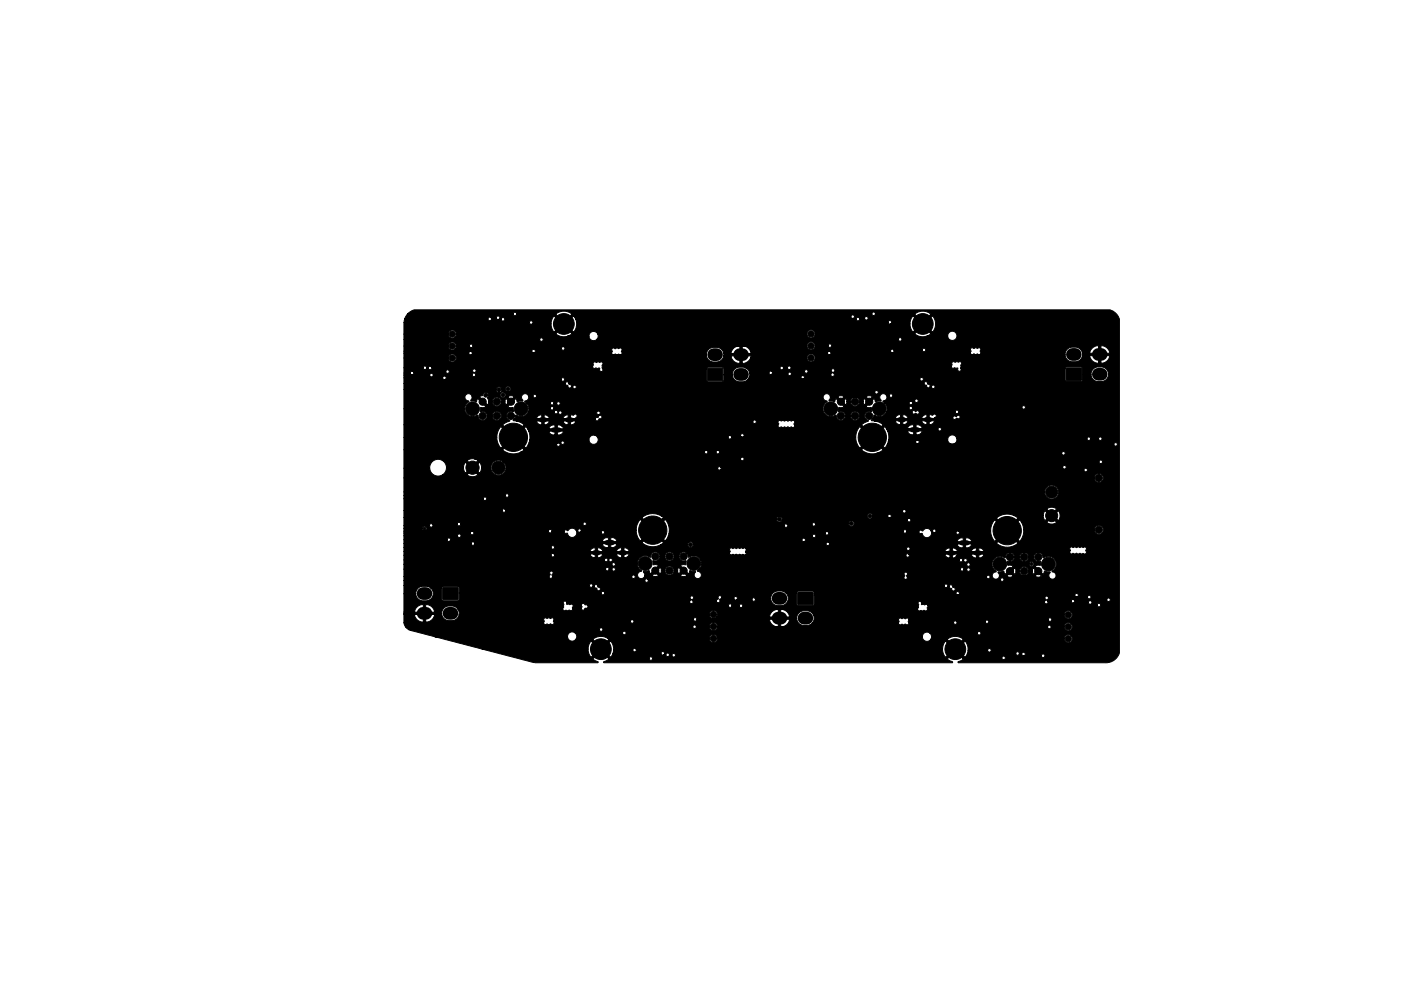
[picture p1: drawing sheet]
<svg xmlns="http://www.w3.org/2000/svg" width="297mm" height="210mm" viewBox="0 0 297 210" stroke-linecap="round" stroke-linejoin="round" font-family="sans-serif">
<g fill="#000" stroke="#000" stroke-width=".21">
<path d="M86.4 66.6l.7-.6 .8-.3 147.6 .1a2.97 2.97 0 0 1 1.8 1.9v70.8a2.99 2.99 0 0 1-2.8 2.1h-31.3l-.1-.1 1.2-.7-.3-.2h8.4a.38 .38 0 0 0 .5 .3 .38 .38 0 0 0 .1-.6 .38 .38 0 0 0-.6 .2v.1h-8.4l-1.5-1.5-1.7 1.7 1.2 .6-.1 .2h-73.8l-.1-.1 .9-.5 .2-.2-.1-.1h8.6a.38 .38 0 0 0 .5 .4 .38 .38 0 0 0 .1-.7 .38 .38 0 0 0-.6 .2v.1h-8.6l-1.6-1.6-1.7 1.7 1.1 .6-.1 .2h-13.2l-11.3-2.9h22.5l.1 1 .5 .8 1.7-1.8h.8l1.7 1.8 .5-.9h10.1l.3 .4 .8-.1v.1a.37 .37 0 0 0 .4 .3 .37 .37 0 0 0 .3-.3h.6v.1a.38 .38 0 0 0 .6 .2 .38 .38 0 0 0-.1-.6 .38 .38 0 0 0-.5 .3l-.6-.1a.38 .38 0 0 0-.3-.3 .38 .38 0 0 0-.4 .3h-.5a.37 .37 0 0 0 0-.6 .37 .37 0 0 0-.6 .3h-10.1l.1-.7h4.1v.1a.37 .37 0 0 0 .5 .3 .37 .37 0 0 0 .2-.6h64.9l.2 1 .5 .8 1.7-1.8h.7l1.7 1.8 .5-.8h10.3a.37 .37 0 0 0 .3 .3 .37 .37 0 0 0 .4-.2h.5l.4 .3h3.8a.38 .38 0 0 0 .5 .4 .38 .38 0 0 0 .1-.7 .38 .38 0 0 0-.6 .2v.1h-3.7a.38 .38 0 0 0 .1-.6 .38 .38 0 0 0-.6 .3h-.5a.38 .38 0 0 0-.3-.5 .38 .38 0 0 0-.4 .4h-10.3l.1-.7h4.2v.1a.38 .38 0 0 0 .6 .1 .38 .38 0 0 0-.1-.6 .38 .38 0 0 0-.5 .4h-4.2l-.1-1.2-.5-.8-1.7 1.7h-.7l-1.7-1.7-.5 .8-.2 .9h-64.9l-.4-.2-.3 .4h-4.1a2.63 2.63 0 0 0-.6-1.9l-1.7 1.7h-.8l-1.7-1.7-.4 .8-.2 .9h-22.5l-10-2.6h28.1l.1 .2a.98 .98 0 0 0 .7 .7 .98 .98 0 0 0 1-.4h3.6l1.7 1.8 1.7-1.7-.2-.2h21.5a.86 .86 0 0 0 .6 .8h.3l.5-.2 .3-.5v-.5h43.5a.98 .98 0 0 0 .7 .9 .98 .98 0 0 0 1-.4h3.5l1.7 1.8 1.8-1.7-.2-.2h21.5l.2 .6a.86 .86 0 0 0 1.3 .1 .86 .86 0 0 0 0-1.3 .86 .86 0 0 0-1.2 0l-.3 .6h-21.5a2.7 2.7 0 0 0-3.3 .1h-3.5l.2-.6-.3-.7h10a.38 .38 0 0 0 .5 .4 .38 .38 0 0 0 .1-.6 .38 .38 0 0 0-.6 .1v.1h-10a.98 .98 0 0 0-1.1-.1 .98 .98 0 0 0-.5 .9h-43.5l-.4-.4-.5-.1-.6 .4-.2 .5h-21.5l-.2-.2a2.69 2.69 0 0 0-3 .3h-3.6a1 1 0 0 0-.1-1.3h10v.1a.38 .38 0 0 0 .6 .2 .38 .38 0 0 0-.1-.6 .38 .38 0 0 0-.5 .3h-10.1a.98 .98 0 0 0-1-.1 .98 .98 0 0 0-.6 .9h-28.1l-5.6-1.5h40.5a.38 .38 0 0 0 .5 .3 .38 .38 0 0 0 .1-.6 .38 .38 0 0 0-.6 .2v.1h-40.5l-.6-.6h60.9a.37 .37 0 0 0 .4 .3 .37 .37 0 0 0 .3-.4h2.8l.2 .6a.86 .86 0 0 0 .9 .3 .86 .86 0 0 0 .6-.7l70-.1v.1a.37 .37 0 0 0 .5 .3 .37 .37 0 0 0 .3-.4h2.7a.86 .86 0 0 0 1.3 .7 .86 .86 0 0 0 .1-1.4 .86 .86 0 0 0-1.4 .5v.2h-2.7a.37 .37 0 0 0-.4-.4 .37 .37 0 0 0-.4 .4h-70v-.3a.85 .85 0 0 0-1.4-.4l-.3 .6h-2.8a.37 .37 0 0 0-.4-.3 .37 .37 0 0 0-.3 .4h-60.9l-.4-.9h29.7v.2a.53 .53 0 0 0 .8 .1l.2 .1 .5-.1a.39 .39 0 0 0 .5 0 .39 .39 0 0 0 0-.6h16.4v.2a.38 .38 0 0 0 .6 .1 .38 .38 0 0 0-.1-.6 .38 .38 0 0 0-.5 .3h-16.4l.2-.4h29.5v.1a.37 .37 0 0 0 .4 .3 .37 .37 0 0 0 .4-.4l15.3 .1a1.82 1.82 0 0 0 1.9 1.5h.5a1.81 1.81 0 0 0 1.9-1.6h-1.9v1.6h-.5v-1.6h-17.2a.37 .37 0 0 0-.4-.4 .37 .37 0 0 0-.4 .4l-29.6-.1a.52 .52 0 0 0-.8-.1l-.3-.1-.2 .1a.5 .5 0 0 0-.8 .2l.1 .4-.1 .3h-29.7v-1.7h2.3a1.82 1.82 0 0 0 1.9 1.6h.5a1.81 1.81 0 0 0 1.8-1.6h-1.8v1.6h-.5l-.1-1.6h-4.1v-.2h8.1a1.55 1.55 0 0 0 1.4 1.5h.8a1.54 1.54 0 0 0 1.4-1.3h53.1v.2a.85 .85 0 0 0 1.1 .6h17.4v.3a1.57 1.57 0 0 0 1.4 1.2l1.3-.1 .6-.4h18.3v.1a.53 .53 0 0 0 .8 .2l.3 .1 .4-.2a.38 .38 0 0 0 .5 .1 .38 .38 0 0 0 .2-.4h9.5v.1a.37 .37 0 0 0 .5 .2 .37 .37 0 0 0 .2-.5h6v.1a.38 .38 0 0 0 .6 .2 .38 .38 0 0 0-.1-.6 .38 .38 0 0 0-.5 .3h-6l-.4-.2-.3 .4h-9.5l-.2-.2 .2-.4h29.5a.38 .38 0 0 0 .6 .3 .38 .38 0 0 0 .1-.6 .38 .38 0 0 0-.6 .1l-.1 .2h-29.5a.44 .44 0 0 0-.3-.4 .44 .44 0 0 0-.5 .2l-.3-.2-.4 .2a.44 .44 0 0 0-.6-.1 .44 .44 0 0 0 0 .7l-.1 .3h-18.3l.1-.2a1.55 1.55 0 0 0 .1-1.6h53.2a.86 .86 0 0 0 .8 .9 .86 .86 0 0 0 .9-.7v-.4a.85 .85 0 0 0-1.4-.4l-.3 .6h-53.2l-.7-.7-1.3-.1a1.56 1.56 0 0 0-1.5 1.6h-17.4l.5-.3h15.4a1.83 1.83 0 0 0-1.9-1.6v1.6h-.5v-1.6a1.85 1.85 0 0 0-1.9 1.6h-11.1v-.2a.86 .86 0 0 0-.2-1 .86 .86 0 0 0-1.1 0l-.3 .7h-53.1v-.6l-.2-.6h22.2a.48 .48 0 0 0 .8 .3h.5a.5 .5 0 0 0 .8-.3v-.1h1.9l.3 .4 .4-.3h70.5a.48 .48 0 0 0 .8 .3h.5a.5 .5 0 0 0 .8-.3l.1-.8h35.9v.1a.38 .38 0 0 0 .6 .2 .38 .38 0 0 0-.1-.7 .38 .38 0 0 0-.5 .4h-35.9l-.3-.2-.3 .1h-.7l-.1-.6h26.1l.1 .2a.37 .37 0 0 0 .5 .2 .37 .37 0 0 0 .1-.6h5l.4 .4 3.3-.1a.38 .38 0 0 0 .5 .4 .38 .38 0 0 0 .1-.7 .38 .38 0 0 0-.6 .2v.1h-3.1l.2-.3-.2-.3h7v.2a.38 .38 0 0 0 .6 .1 .38 .38 0 0 0-.1-.6 .38 .38 0 0 0-.5 .3h-7.2l-.4 .3h-5l-.1-.2 .3-.3-.1-.3h8.4a.38 .38 0 0 0 .5 .3 .38 .38 0 0 0 .1-.6 .38 .38 0 0 0-.6 .2v.1h-8.4a.4 .4 0 0 0-.6 0 .4 .4 0 0 0 .2 .6l-.4 .4h-26.1a.42 .42 0 0 0-.6 0 .42 .42 0 0 0 .1 .7v.4l-.3 .4h-70.5v-.1a.45 .45 0 0 0 .5-.1 .45 .45 0 0 0 .1-.5h29.8l.1 .1a.37 .37 0 0 0 .4 .3 .37 .37 0 0 0 .3-.4h1.5v.1a.38 .38 0 0 0 .7 .2 .38 .38 0 0 0-.1-.6 .38 .38 0 0 0-.6 .3h-1.5a.38 .38 0 0 0-.4-.4 .38 .38 0 0 0-.4 .4h-29.8l-.4-.2a.49 .49 0 0 0-.5-.3 .49 .49 0 0 0-.4 .3l.1 .4-.1 .4h-1.9l-.1-.2a.43 .43 0 0 0 .1-.6 .43 .43 0 0 0-.6 0l-.6-.1-.1-.5h26.1a.37 .37 0 0 0 .5 .4 .37 .37 0 0 0 .2-.6h5v.1a.42 .42 0 0 0 .6 .2 .42 .42 0 0 0 .1-.7l.3-.2h2.7l.4 .4 3.4-.1v.1a.37 .37 0 0 0 .6 .2 .37 .37 0 0 0 .1-.5h3.3a1.56 1.56 0 0 0 1.5 1.5h.7a1.55 1.55 0 0 0 1.5-1.9l-.5-.8h2.3v2.3l.1 .3 .3 .1h2.9l.4-.4v-1.8h55.3v.1a.38 .38 0 0 0 .6 .2 .38 .38 0 0 0-.1-.7 .38 .38 0 0 0-.5 .4h-55.3v-.4h30.1v.1a.38 .38 0 0 0 .6 .2 .38 .38 0 0 0-.1-.7 .38 .38 0 0 0-.5 .4h-30.1l-.1-.4-.3-.1h-2.9l-.4 .4h-2.3l-.6-.4h-1.1a1.55 1.55 0 0 0-1.5 1.6h-3.3l-.3-.2-.4 .4-3.1-.1a.37 .37 0 0 0-.2-.5 .37 .37 0 0 0-.5 .3h-2.7a.41 .41 0 0 0-.4-.5 .41 .41 0 0 0-.2 .7l-.4 .4h-5l-.2-.3a.39 .39 0 0 0 .4-.5 .39 .39 0 0 0-.7-.2 .39 .39 0 0 0 .1 .7l-.3 .5h-26.1a.42 .42 0 0 0-.6 0 .42 .42 0 0 0 0 .6v.5l-.2 .4h-22.2l-.9-.6h-1.1a1.56 1.56 0 0 0-1.4 1.6h-8.1v-.3h6.5a1.83 1.83 0 0 0-1.8-1.6v1.6h-.5l-.1-1.6a1.85 1.85 0 0 0-1.8 1.6h-2.3v-3.9h2.6a1.56 1.56 0 0 0 1.4 1.5h.8a1.55 1.55 0 0 0 1.4-1.9l-.5-.8h2.4v2.3l.4 .4 3-.1 .3-.3v-1.3h30l.1 .2a.38 .38 0 0 0 .6 .1 .38 .38 0 0 0-.1-.6 .38 .38 0 0 0-.6 .3h-30v-1.1l-.4-.3h-3l-.3 .4h-2.4l-.8-.4-1.3 .1a1.55 1.55 0 0 0-1 1.5h-2.6v-1.8h39.4l.2 .4 .8-.2 .2 .3 .3 .1a.41 .41 0 0 0 .4 .5 .41 .41 0 0 0 .4-.5l-.5-.3-.1-.2h73.5l.3 .3 .7-.2 .2 .3 .3 .1a.41 .41 0 0 0 .4 .6 .41 .41 0 0 0 .4-.6l-.1-.1a.56 .56 0 0 1-.6-.6h-.3l-.3 .3h-.3a.37 .37 0 0 0-.2-.5 .37 .37 0 0 0-.5 .4h-73.5a.38 .38 0 0 0-.4-.3 .38 .38 0 0 0-.3 .4h-.3a.37 .37 0 0 0-.3-.5 .37 .37 0 0 0-.4 .3h-39.4v-1h51.1v.1a.37 .37 0 0 0 .5 .2 .37 .37 0 0 0 .2-.5h74.7v.1a.38 .38 0 0 0 .6 .2 .38 .38 0 0 0-.1-.7 .38 .38 0 0 0-.5 .4h-74.7l-.3-.2-.4 .4h-51.1v-.9h30.8v.2a.37 .37 0 0 0 .4 .2 .37 .37 0 0 0 .3-.3h16.8l.1 .1a.38 .38 0 0 0 .6 .1 .38 .38 0 0 0-.1-.6 .38 .38 0 0 0-.6 .4l-16.7-.1a.56 .56 0 0 1 .1-.8 .41 .41 0 0 0-.7-.3 .41 .41 0 0 0 .1 .7l-.3 .4h-30.8v-1.6h42.8v.2a.37 .37 0 0 0 .4 .2 .37 .37 0 0 0 .3-.3h.6l.1 .1a.38 .38 0 0 0 .6 .2 .38 .38 0 0 0-.1-.6 .38 .38 0 0 0-.6 .3l-.6-.1a.38 .38 0 0 0-.3-.3 .38 .38 0 0 0-.4 .3h-42.8v-1h44.1l.1 .1a.37 .37 0 0 0 .4 .3 .37 .37 0 0 0 .2-.5h4.7l.2 .7 .7 .9a.78 .78 0 0 0-.8 .7 .78 .78 0 0 0 .6 .8 .78 .78 0 0 0 .9-.6h1.6a1.24 1.24 0 0 0 1.3 0h4.7a1.2 1.2 0 0 0 1.3 0l-.7-.7-.7 .7h-4.6l-.7-.7-.7 .7h-1.5l-.3-.7 .1-.2 1.1-.1 .3 .7 .7-.7h.7l.7 .7 .2-.8h.8a.97 .97 0 0 0 .9 1 .97 .97 0 0 0 1-.9h.8l.2 .7 .7-.7-.7-.7-.2 .7h-.8a.97 .97 0 0 0-.9-1 .97 .97 0 0 0-1 .9h-.8l-.2-.6-.7 .7h-.7l1-1.1-.4-.2h-.7l-.1-.7 .1-.2a.98 .98 0 0 0 1.4-.9l1.1 .1a.96 .96 0 0 0 .9 .9 .96 .96 0 0 0 1-1l1.1 .1a1.03 1.03 0 0 0 1.5 .9l-.1 .8h-.7l-.4 .2 1.7 1.8 .3-.7 1.2 .2a.78 .78 0 0 0-.2 1.2 .78 .78 0 0 0 1.2 .1h43.1v.1a.37 .37 0 0 0 .5 .2 .37 .37 0 0 0 .3-.5h16.8v.1a.38 .38 0 0 0 .6 .2 .38 .38 0 0 0-.1-.6 .38 .38 0 0 0-.5 .3h-16.8l-.2-.3a.39 .39 0 0 0 .2-.6 .39 .39 0 0 0-.6 0 .39 .39 0 0 0 .1 .6l-.3 .5h-43.1a.83 .83 0 0 0 .1-.9 .83 .83 0 0 0-.7-.5l.3-.4h55.4v.1a.37 .37 0 0 0 .4 .3 .37 .37 0 0 0 .4-.4h.6v.2a.38 .38 0 0 0 .6 .1 .38 .38 0 0 0-.1-.6 .38 .38 0 0 0-.5 .3h-.6a.38 .38 0 0 0-.4-.4 .38 .38 0 0 0-.4 .4h-55.4l.4-.5 .1-.5h56.3a.37 .37 0 0 0 .4 .3 .37 .37 0 0 0 .3-.4h4.6l.2 .7 .7 .8-.1 .2a.77 .77 0 0 0-.7 .7 .77 .77 0 0 0 .6 .8 .77 .77 0 0 0 .9-.7h1.6a1.24 1.24 0 0 0 1.3 0h4.7a1.2 1.2 0 0 0 1.3 0l-.7-.7-.7 .7h-4.6l-.7-.7-.7 .7h-1.5l-.3-.7 .1-.2 1.1-.1 .3 .7 .7-.7h.7l.7 .7 .2-.7h.8a.96 .96 0 0 0 .9 .9 .96 .96 0 0 0 1-.9h.8l.2 .7 .7-.7-.7-.7-.2 .7h-.8a.96 .96 0 0 0-1-1 .96 .96 0 0 0-.9 1h-.8l-.2-.7-.7 .7h-.7l1-1.1-.4-.2-.7 .1-.1-.4 4.6 .1a.51 .51 0 0 0 .7 .4 .51 .51 0 0 0 .1-.8 .51 .51 0 0 0-.8 .2v.1h-4.6v-.5a1.06 1.06 0 0 0 1.5-.7v-.2h1.1a.96 .96 0 0 0 1 .9 .96 .96 0 0 0 .9-.9h1.1a1.04 1.04 0 0 0 1.5 .9l-.1 .8h-.7l-.5 .2 1.8 1.8 .3-.7 1.2 .3a.8 .8 0 0 0 .1 1.3 .8 .8 0 0 0 1.2-.6 .8 .8 0 0 0-1-.9 1.87 1.87 0 0 0 .8-2.4 1.66 1.66 0 0 0-2.5-.6h-.2a.98 .98 0 0 0-.9-1.1 .98 .98 0 0 0-1 1h-1.1v-.2a.97 .97 0 0 0-1.1-.8 .97 .97 0 0 0-.8 1h-1.1v-.2a1 1 0 0 0-1.2-.8 1 1 0 0 0-.8 1.2l-.1-.1a1.66 1.66 0 0 0-2.7 1.4h-4.6a.38 .38 0 0 0-.4-.3 .38 .38 0 0 0-.3 .4h-56.3l-.1-1h54.8l.3 .4 .6-.3a.38 .38 0 0 0 .4 .4 .38 .38 0 0 0 .3-.5 .38 .38 0 0 0-.6-.1l-.3 .1a.38 .38 0 0 0-.4-.3 .38 .38 0 0 0-.3 .3h-54.8a1.8 1.8 0 0 0-2.6-.6l-.1-.4h46.2v.2a.37 .37 0 0 0 .5 .2 .37 .37 0 0 0 .1-.6h7.6v.1a1.02 1.02 0 0 0 1.1 .7h.5a1.01 1.01 0 0 0 1.1-.8h2.9v.1a1.02 1.02 0 0 0 1.1 .7h.5a1 1 0 0 0 1.1-.8h-1.1v.8h-.5v-.8h-5.1v.8h-.5v-.8h-8.7l-.3-.1-.3 .3h-46.2l-.3-.4h9.1v.1a.53 .53 0 0 0 .8 .1l.2 .1 .4-.1 .4 .1 .3-.1 .4 .1 .3-.1a.41 .41 0 0 0 .5 .1 .41 .41 0 0 0 .1-.5h68.7v.1a.53 .53 0 0 0 .8 .1l.3 .1 .3-.1 .4 .1 .3-.1 .4 .1 .2-.1a.5 .5 0 0 0 .8-.2l-.1-.4a.46 .46 0 0 0 0-.6 .46 .46 0 0 0-.6-.1l-.3-.1-.4 .2-.3-.2-.3 .2-.4-.2-.3 .1a.5 .5 0 0 0-.8 .3l.2 .4-.2 .4-68.7-.1h50.5a1.01 1.01 0 0 0-1.1-.8v.7h-.5v-.7a1 1 0 0 0-1.1 .8h-2.9a1.02 1.02 0 0 0-1.1-.8v.7h-.5v-.7a1.04 1.04 0 0 0-1.1 .8l-42.3-.1 .2-.6h34a.38 .38 0 0 0 .5 .4 .38 .38 0 0 0 .1-.7 .38 .38 0 0 0-.6 .2v.1h-34l-.2-.1-.5 .1-.3-.2-.3 .2-.4-.2-.4 .2-.4-.2-.2 .2a.5 .5 0 0 0-.8 .2l.1 .4-.1 .4h-9.1a.96 .96 0 0 0-1-.2 .96 .96 0 0 0-.6 .8h-1.1v-.1a.97 .97 0 0 0-1-.8 .97 .97 0 0 0-.9 .9h-1.1v-.1a1 1 0 0 0-1.2-.8 1 1 0 0 0-.8 1.1 1.74 1.74 0 0 0-2.8 1.4h-4.7l-.3-.2-.4 .3h-44.1v-.9h42.5l.1 .1a.44 .44 0 0 0 .4 .3 .44 .44 0 0 0 .4-.4l.1 .1a.37 .37 0 0 0 .6 .3 .37 .37 0 0 0 0-.7 .37 .37 0 0 0-.6 .2h-.2a.37 .37 0 0 0-.4-.3 .37 .37 0 0 0-.4 .4h-42.5v-1h31.2v.1a.37 .37 0 0 0 .6 .2 .37 .37 0 0 0 .1-.6h7.6v.2a1.02 1.02 0 0 0 1.1 .6h.5a1.01 1.01 0 0 0 1.1-.8h2.9v.2a1.02 1.02 0 0 0 1.1 .6h.5a1 1 0 0 0 1.1-.8h-1.1v.8h-.5v-.8h-5.1v.8h-.5v-.8h-8.7l-.3-.1-.4 .4h-31.2v-.8h47.8a1.01 1.01 0 0 0-1.1-.8v.8h-.5v-.8a1 1 0 0 0-1.1 .8h-2.9a1.02 1.02 0 0 0-1.1-.8v.8h-.5v-.8a1.04 1.04 0 0 0-1.1 .8h-39.5v-.9h31.2v.2a.38 .38 0 0 0 .7 .1 .38 .38 0 0 0-.1-.6 .38 .38 0 0 0-.6 .3h-31.2v-.8h14.3v.1a.37 .37 0 0 0 .4 .3 .37 .37 0 0 0 .3-.3h27.1l.2 .5 .4 .2 1.5 .1 .7-.3 .3-.5h-1.3v.8h-.5v-.8h-28.4v-.3h35.5a3.5 3.5 0 0 0 4 .4l5.7 .1a.6 .6 0 0 0 .7 .5 .6 .6 0 0 0 .5-.7h28.1v.1a.37 .37 0 0 0 .4 .2 .37 .37 0 0 0 .4-.3h27l.3 .5 .3 .2 1.6 .1 .7-.3 .2-.5h-1.3v.8h-.5v-.8h-28.3l-.1-.2h35.5a3.5 3.5 0 0 0 4.5 0l-2.3-2.2-2.2 2.2h-35.5l-.3-.2-.4 .4h-28.1a.6 .6 0 0 0-.7-.5 .6 .6 0 0 0-.5 .6h-5.7l.6-.4-2.3-2.2-2.3 2.2h-35.5l-.3-.2-.4 .4h-14.3v-.8h9.2l.4 .4h35.6a1 1 0 0 0-.9-.8h-.4v.8h-.5v-.8h-.4l-.7 .3-.2 .5h-32.4a.38 .38 0 0 0 .1-.7 .38 .38 0 0 0-.6 .3h-9.2v-.8h11.4v.1a.38 .38 0 0 0 .6 .1 .38 .38 0 0 0-.1-.6 .38 .38 0 0 0-.5 .4h-11.4v-.6h14.1v.1a.38 .38 0 0 0 .6 .2 .38 .38 0 0 0-.1-.6 .38 .38 0 0 0-.5 .3h-14.1v-.4h30.7v.1a.37 .37 0 0 0 .4 .3 .37 .37 0 0 0 .3-.3h2.6l.2 .3a.49 .49 0 0 1 .7 .6 .98 .98 0 0 0 1.3 .2 .98 .98 0 0 0 .4-1.3h.3l.4 .3h4.5a.38 .38 0 0 0 .6 .4 .38 .38 0 0 0 .1-.6 .38 .38 0 0 0-.6 .1l-.1 .1h-4.5l.3-.1v-.3h11.7l.2 1.1 .6 1.2 2.3-2.3h.8l2.3 2.3 .1-.2h28.8l.4 .3h35.6a1 1 0 0 0-.9-.8h-.4v.8h-.5v-.8h-.3l-.7 .3-.3 .5h-32.4a.38 .38 0 0 0 .1-.6 .38 .38 0 0 0-.6 .3h-28.8l.5-.9h30.5v.1a.38 .38 0 0 0 .6 .2 .38 .38 0 0 0-.1-.6 .38 .38 0 0 0-.5 .3h-30.5l.1-.6h33.1l.1 .2a.38 .38 0 0 0 .6 .1 .38 .38 0 0 0-.1-.6 .38 .38 0 0 0-.6 .3h-33.1l.1-.4h49.6v.2a.37 .37 0 0 0 .4 .2 .37 .37 0 0 0 .3-.3h2.6l.3 .4h.4l.3 .5a.98 .98 0 0 0 1.3 .2 .98 .98 0 0 0 .3-1.2l.3-.1 .4 .4h4.6v.1a.38 .38 0 0 0 .6 .2 .38 .38 0 0 0-.1-.6 .38 .38 0 0 0-.5 .3h-4.6l.3-.2 .1-.2h11.5l.2 1.1 .7 1.2 2.3-2.3h.7l2.3 2.3a3.4 3.4 0 0 0 .8-2.5h15a.95 .95 0 0 0 1.4 .9 .95 .95 0 0 0 .2-1.6 .95 .95 0 0 0-1.6 .5v.2h-15l-.4-1.6h5.3a1.72 1.72 0 0 0 2.1 0l-1-1-1.1 1h-5.3l-.4-.5-2.3 2.3h-.7l-2.3-2.3-.7 1.2-.2 1.1h-11.5a.37 .37 0 0 0-.4-.4 .37 .37 0 0 0-.4 .4h-.3l-.2-.2a1.06 1.06 0 0 0-1.6 .3 .41 .41 0 0 0-.5-.2 .41 .41 0 0 0-.3 .3l-2.6-.1a.38 .38 0 0 0-.3-.3 .38 .38 0 0 0-.4 .3h-49.6l-.1-1.2h24.5v.1a.37 .37 0 0 0 .5 .2 .37 .37 0 0 0 .1-.6h5.3v.2a.37 .37 0 0 0 .5 .2 .37 .37 0 0 0 .2-.6h7v.2a.61 .61 0 0 0 1 .3 .61 .61 0 0 0-.1-1 .61 .61 0 0 0-.9 .5h-7l-.4-.1-.3 .3-5.6-.1-.3 .4h-24.5l-.7-1.3-2.3 2.3h-.8l-2.2-2.3a3.3 3.3 0 0 0-.9 2.3h-11.7a.38 .38 0 0 0-.4-.3 .38 .38 0 0 0-.3 .4h-.3l-.2-.2a1.06 1.06 0 0 0-1.6 .2 .41 .41 0 0 0-.5-.2 .41 .41 0 0 0-.3 .4l-2.6-.1a.38 .38 0 0 0-.4-.4 .38 .38 0 0 0-.3 .4h-30.7v-.6h3.9l.3 .5a.5 .5 0 0 0 .7-.3 .5 .5 0 0 0-.4-.6 .5 .5 0 0 0-.6 .4h-3.9v-.6h5.4l.1 .1a.37 .37 0 0 0 .5 .2 .37 .37 0 0 0 .1-.6h5.2l.1 .1a.37 .37 0 0 0 .4 .3 .37 .37 0 0 0 .3-.5h25.9v.2a.38 .38 0 0 0 .6 .1 .38 .38 0 0 0-.1-.6 .38 .38 0 0 0-.5 .3h-25.9a.38 .38 0 0 0-.4-.3 .38 .38 0 0 0-.4 .4l-5.5-.1-.4 .4h-5.4v-1.7h50.5l2.3 2.3 2-2h24.2l.1 .2a.6 .6 0 0 0 .5 .5 .6 .6 0 0 0 .6-.4h26.6v.1a.38 .38 0 0 0 .6 .1 .38 .38 0 0 0-.1-.6 .38 .38 0 0 0-.5 .4l-26.6-.1a.61 .61 0 0 0-.5-.8 .61 .61 0 0 0-.7 .6h-24.2l.3-.3-.5-.3h43.6a.6 .6 0 0 0 .4 .5 .6 .6 0 0 0 .7-.1h26.4l2.2 2.3 2.3-2.3-.9-.5h6.3l.3 1.1 1.1-1.1h.7l1.1 1.1a1.72 1.72 0 0 0 0-2.2l-1.1 1.1h-.7l-1.1-1.1-.3 1.1h-6.3l-.3-.2a3.5 3.5 0 0 0-3.3 .7h-26.4l.2-.4h3.1a.38 .38 0 0 0 .5 .3 .38 .38 0 0 0 .1-.6 .38 .38 0 0 0-.6 .2v.1h-3.1a.61 .61 0 0 0-.6-.6 .61 .61 0 0 0-.7 .6l-43.6-.1a3.5 3.5 0 0 0-4.1 .4h-50.5v-1.5h20.9l.4 .4 .3-.2h84.1l.1 .1a.38 .38 0 0 0 .6 .2 .38 .38 0 0 0-.1-.7 .38 .38 0 0 0-.6 .4h-84.1v-.3l-.2-.2h114.9l1.1 1 1-1a1.72 1.72 0 0 0-2.1 0l-115-.1-.4 .4h-20.9v-2.5h16.8a.38 .38 0 0 0 .6 .4 .38 .38 0 0 0 .1-.7 .38 .38 0 0 0-.6 .2l-.1 .1h-16.8v-.7h21.5a.38 .38 0 0 0 .6 .4 .38 .38 0 0 0 .1-.7 .38 .38 0 0 0-.7 .2v.1h-21.5v-.7h135.9a1.48 1.48 0 0 0 2.1 1.3 1.48 1.48 0 0 0 .3-2.5 1.48 1.48 0 0 0-2.4 .9v.3h-135.9v-3h146.4a.95 .95 0 0 0 1.4 .9 .95 .95 0 0 0 .2-1.6 .95 .95 0 0 0-1.6 .5v.2h-146.4v-2.1h5.5a1.78 1.78 0 0 0 2.7 1.4l5.2 .1a1.86 1.86 0 0 0 2.3-.1l-1.1-1.1-1.2 1.1h-5.1a1.77 1.77 0 0 0 .8-1.5h3.6v.5l.4 .7 1.1-1.2h.7l1.2 1.2 .4-1.2h2v.3a1.6 1.6 0 0 0 1.6 1.3 1.6 1.6 0 0 0 1.6-1.4h44.9l.3 .4 77.3-.1a.38 .38 0 0 0 .5 .4 .38 .38 0 0 0 .1-.7 .38 .38 0 0 0-.6 .2v.1h-77.1l.2-.2-.1-.4h72.5v.1a.38 .38 0 0 0 .6 .2 .38 .38 0 0 0-.1-.6 .38 .38 0 0 0-.5 .3h-72.5l-.3-.1-.3 .4h-44.9l-.2-.9-.4-.5h126.3a.38 .38 0 0 0 .5 .3 .38 .38 0 0 0 .1-.6 .38 .38 0 0 0-.6 .2v.1l-126.4-.1a1.61 1.61 0 0 0-1.6-.1 1.61 1.61 0 0 0-.9 1.4h-2l-.4-1.1-1.2 1.1h-.7l-1.1-1.1-.4 1.1h-3.6l-.3-.8-.6-.7h5.2l1.2 1.2 1.1-1.2-.6-.3h56.3v.1a.38 .38 0 0 0 .6 .2 .38 .38 0 0 0-.1-.7 .38 .38 0 0 0-.5 .4l-56.8-.1-1.2 .4h-5.2a1.78 1.78 0 0 0-2.7 1.6h-5.5v-3.9l21 .1a3.5 3.5 0 0 0 3.8 .4h39v.1a.38 .38 0 0 0 .4 .3 .38 .38 0 0 0 .3-.4h1.7v.1a.38 .38 0 0 0 .6 .2 .38 .38 0 0 0-.1-.6 .38 .38 0 0 0-.5 .3h-1.7v-.1a.38 .38 0 0 0-.4-.2 .38 .38 0 0 0-.3 .3h-39l.7-.5h71.6a3.5 3.5 0 0 0 3.1 .8h39.3v.1a.38 .38 0 0 0 .6 .2 .38 .38 0 0 0-.1-.7 .38 .38 0 0 0-.5 .4h-39.3l1.4-.8-2.3-2.2-2.2 2.2h-71.6l-2.3-2.2-2.2 2.2h-21v-2.6h19.7l.2 1.1 .7 1.2 2.3-2.3h.7l2.3 2.3 .5-.8h6v.1a.38 .38 0 0 0 .5 .3 .38 .38 0 0 0 .2-.6l-.4-.1-.3 .3h-6l.2-.4h6.7v.2a.4 .4 0 0 0 .5 .2 .4 .4 0 0 0 .3-.4 .38 .38 0 0 0-.4-.3 .38 .38 0 0 0-.4 .3h-6.7l.1-.6h12.6l.3 .7a.99 .99 0 0 0 1.5-.2l.1-.5-.1-.5h27.7v.1a.37 .37 0 0 0 .4 .2 .37 .37 0 0 0 .3-.3h26.3l.2 1.1 .7 1.2 2.3-2.3h.7l2.3 2.3 .5-.8h48.1a.38 .38 0 0 0 .5 .3 .38 .38 0 0 0 .1-.6 .38 .38 0 0 0-.6 .2v.1h-48.1l.2-.6h5.8a.38 .38 0 0 0 .6 .4 .38 .38 0 0 0 .1-.6 .38 .38 0 0 0-.7 .1v.1h-5.8l.1-.4h12.5a.98 .98 0 0 0 1.1 .9 .98 .98 0 0 0 .9-1.1h27.6v.1a.38 .38 0 0 0 .4 .2 .38 .38 0 0 0 .3-.3h1.7v.1a.38 .38 0 0 0 .6 .2 .38 .38 0 0 0-.1-.7 .38 .38 0 0 0-.5 .4h-1.7v-.1a.38 .38 0 0 0-.4-.3 .38 .38 0 0 0-.3 .4h-27.6l-.1-.3a.98 .98 0 0 0-1.1-.5 .98 .98 0 0 0-.8 1h-12.5v-.9l-.2-1h4.2l.3 .5 .3 .3h1.6l.7-.3 .2-.5h-1.3v.8h-.5v-.8h-5.5l-.2-.3h10.9v.1a.38 .38 0 0 0 .6 .1 .38 .38 0 0 0-.1-.6 .38 .38 0 0 0-.5 .4h-10.9l-.1-.2h7.6a1 1 0 0 0-.9-.8h-.4v.8h-.5v-.8l-.9 .2-.4 .6h-4.5l-.3-.4-2.3 2.3h-.7l-2.3-2.3-.7 1.2-.2 1.1h-26.3a.37 .37 0 0 0-.4-.4 .37 .37 0 0 0-.3 .4h-27.7l-.5-.4h30.8v.1a.38 .38 0 0 0 .6 .2 .38 .38 0 0 0-.1-.7 .38 .38 0 0 0-.5 .4h-30.8a.98 .98 0 0 0-1.3 .9h-12.6v-.9l-.2-.9h4.2l.3 .5 .4 .2 1.5 .1 .7-.3 .3-.5h-1.3v.8h-.5l-.1-.8h-5.5l-.3-.5h7.7l-.5-.7h45.9a.48 .48 0 0 0 .8 .3l.3 .1 .4-.1 .3 .1 .3-.2 .4 .2 .3-.1a.5 .5 0 0 0 .8-.3l-.1-.2h14.3l2.2 2.3 2.3-2.3-.8-.5-1.1-.3h4.5v.1a1.02 1.02 0 0 0 1.1 .7h.5a1.01 1.01 0 0 0 1.1-.8h2.9v.1a1.02 1.02 0 0 0 1.1 .7h.5a1 1 0 0 0 1.1-.8h-1.1v.8h-.5v-.8h-5.1v.8h-.5v-.8h-5.6l-.6-.2 .4-.3h13l.1-.2h3.8a.43 .43 0 0 0 .4 .4 .43 .43 0 0 0 .4-.3 .39 .39 0 0 0 .7 .1 .39 .39 0 0 0-.1-.6 .39 .39 0 0 0-.6 .2 .46 .46 0 0 0-.8 .2h-3.8a.41 .41 0 0 0 .1-.7 .41 .41 0 0 0-.6 .2l-.7-.1v.8h-.5v-.8a1 1 0 0 0-1.1 .8h-2.9a1.02 1.02 0 0 0-1.1-.8v.8h-.5v-.8a1.04 1.04 0 0 0-1.1 .8h-4.7l.2-.7a1.79 1.79 0 0 0 2.6-.6h5.5l.3 .4 .4-.2a.42 .42 0 0 0 .5 .2 .42 .42 0 0 0 .3-.5h7.6v.1a.38 .38 0 0 0 .6 .2 .38 .38 0 0 0-.1-.7 .38 .38 0 0 0-.5 .4h-7.6l-.2-.3-.3 .1a.3 .3 0 0 1-.3 .1 .3 .3 0 0 1-.2-.2l-.4 .1-.1 .3h-5.5l.2-.9h4.6v.1a.37 .37 0 0 0 .5 .2 .37 .37 0 0 0 .2-.5h23.3v.1a.38 .38 0 0 0 .6 .2 .38 .38 0 0 0-.1-.6 .38 .38 0 0 0-.5 .3h-23.3l-.3-.2-.4 .4h-4.6l-.2-.6-.3-.5h5.1v.1a.38 .38 0 0 0 .7 .2 .38 .38 0 0 0-.1-.6 .38 .38 0 0 0-.6 .3h-5.1l-.4-.3 .3-.2h6.4a.38 .38 0 0 0 .6 .4 .38 .38 0 0 0 .1-.7 .38 .38 0 0 0-.7 .2v.1h-6.4l.5-.4v-.7h.5v.1a.38 .38 0 0 0 .7 .2 .38 .38 0 0 0-.1-.6 .38 .38 0 0 0-.6 .3h-.5a.8 .8 0 0 0-1.3-.1 .8 .8 0 0 0 .1 1.2l-1.1 .2-.4-.7-1.7 1.8 .5 .2h.7v.8h-.1a1 1 0 0 0-1.4 .7 1 1 0 0 0 .8 1.3l-1.4 .8h-14.3l-.1-.2a.42 .42 0 0 0 .1-.6 .42 .42 0 0 0-.7 0l-.3-.1-.3 .2-.4-.2-.3 .1-.4-.1-.2 .1a.5 .5 0 0 0-.9 .3l.2 .3-.2 .4h-45.9l-.8-.1v.8h-.5v-.8h-.4l-.7 .3-.3 .5h-4.5l-.3-.5-2.3 2.3h-.7l-2.3-2.3a3.3 3.3 0 0 0-.9 2.3h-19.7v-2.7h21l2.2 2.3 2.3-2.3-.8-.5-.8-.3h4.2l.1 .2a1.02 1.02 0 0 0 1.1 .6h.5a1.01 1.01 0 0 0 1.1-.8h2.8l.1 .2a1.02 1.02 0 0 0 1.1 .6h.5a1.01 1.01 0 0 0 1-.6h37.6a.38 .38 0 0 0 .5 .3 .38 .38 0 0 0 .1-.6 .38 .38 0 0 0-.6 .2v.1h-37.6l.1-.2h-1.1v.8h-.5l-.1-.8h-5v.8h-.5l-.1-.8h-5.3h-.6l-.1-.2 .2-.2h17.2a.42 .42 0 0 0 .5 .4 .42 .42 0 0 0 .3-.5 .42 .42 0 0 0 .6-.3 .42 .42 0 0 0-.5-.4 .46 .46 0 0 0 .1-.6 .46 .46 0 0 0-.4-.3 .42 .42 0 0 0-.3 .6 .42 .42 0 0 0 .5 .2v.2a.48 .48 0 0 1-.5 .4l-.3 .3h-17.2l.1-.1h13v-.2a.42 .42 0 0 0 .1-.6 .42 .42 0 0 0-.7 .1l-.5-.1v.8h-.5v-.8a1 1 0 0 0-1.2 .8h-2.8a1.02 1.02 0 0 0-1.1-.8v.8h-.5v-.8a1.04 1.04 0 0 0-1.2 .8h-4.6l.3-.7a1.79 1.79 0 0 0 2.6-.7h5.5v.1a.53 .53 0 0 0 .9 .1 .38 .38 0 0 0 .5 .4 .38 .38 0 0 0 .2-.6 .38 .38 0 0 0-.6-.1l-.2 .1a.39 .39 0 0 0-.4-.3 .39 .39 0 0 0-.4 .3h-5.5l.1-.8h4.6v.1a.37 .37 0 0 0 .4 .3 .37 .37 0 0 0 .3-.3h57.1v.3a1.74 1.74 0 0 0 2.8 1v.2a.96 .96 0 0 0 1 1 .96 .96 0 0 0 .9-1l1.1 .1a.96 .96 0 0 0 1.5 .8 .96 .96 0 0 0 0-1.7 .96 .96 0 0 0-1.5 .8h-1.1a1.06 1.06 0 0 0-1.4-.9v-.8h.7l.5-.2-1.1-1.1h.7l.7 .7 .3-.7h.7a.96 .96 0 0 0 1 1 .96 .96 0 0 0 .9-1h.8l.2 .7 .7-.7-.7-.7-.2 .7h-.8a.97 .97 0 0 0-.9-.9 .97 .97 0 0 0-1 .9h-.7l-.3-.7-.7 .7h-.7l-.7-.7-.3 .7-1.2-.2 .3-.8h1.6l.7 .7 .7-.7h4.6l.7 .7 .7-.7a1.23 1.23 0 0 0-1.4 0h-4.6a1.24 1.24 0 0 0-1.4 0l-1.6-.1a.79 .79 0 0 0-.9-.5 .79 .79 0 0 0-.6 .9 .79 .79 0 0 0 .9 .6l-.7 .9-.2 .7h-57.1a.37 .37 0 0 0-.3-.5 .37 .37 0 0 0-.4 .4h-4.6l-.1-.6-.3-.5h5a.37 .37 0 0 0 .3 .4 .37 .37 0 0 0 .4-.3h.6v.1a.38 .38 0 0 0 .7 .2 .38 .38 0 0 0-.1-.6 .38 .38 0 0 0-.6 .3l-.6-.1a.38 .38 0 0 0-.3-.3 .38 .38 0 0 0-.4 .3h-5l-.5-.3 .1-.1a.76 .76 0 0 0 .8-1.1h.9v.1a.38 .38 0 0 0 .6 .2 .38 .38 0 0 0-.1-.6 .38 .38 0 0 0-.5 .3h-.9l-.1-.1a.8 .8 0 0 0-1.2-.1 .8 .8 0 0 0 .1 1.2l-1.2 .2-.3-.7-1.8 1.8 .5 .2h.7l.1 .8h-.2a1 1 0 0 0-1.3 .7 1 1 0 0 0 .7 1.2l-1.5 .9h-21v-3.4h12.9a1.73 1.73 0 0 0 2.8 1.3l.1 .2a.96 .96 0 0 0 .9 1 .96 .96 0 0 0 1-1l1.1 .1a.96 .96 0 0 0 1.4 .8 .96 .96 0 0 0 .1-1.7 .96 .96 0 0 0-1.5 .8h-1.1a1.06 1.06 0 0 0-1.5-.9l.1-.8h.7l.4-.2-1.7-1.8-.3 .7-1.1-.1 .2-.9h1.5l1.8 1.7 .2-.7h.8a.96 .96 0 0 0 .9 1 .96 .96 0 0 0 1-1h.8l.2 .7 .7-.7-.7-.7-.2 .7h-.8a.97 .97 0 0 0-1-.9 .97 .97 0 0 0-.9 .9h-.8l-.2-.7a.65 .65 0 0 0 0-1 .65 .65 0 0 0-.9 .1l-.2 .3-.7 .3-1.5-.1a.79 .79 0 0 0-1-.5 .79 .79 0 0 0-.6 .9 .79 .79 0 0 0 .9 .6l-.7 .9-.2 .7h-12.9v-4h19.6a.94 .94 0 0 0 1 .6 .63 .63 0 0 0 0 .9 .63 .63 0 0 0 .9 0h.5l.7 .7 .7-.7a1.23 1.23 0 0 0-1.4 0l-.4-.1a.6 .6 0 0 0-.3-.9h78.6v.1a.38 .38 0 0 0 .6 .2 .38 .38 0 0 0-.1-.6 .38 .38 0 0 0-.5 .3l-79.2-.1 .1-.6h.7v.2a.61 .61 0 0 0 1 .3 .61 .61 0 0 0-.1-1 .61 .61 0 0 0-.9 .5h-.7a.61 .61 0 0 0-.7-.4 .61 .61 0 0 0-.5 .6h-19.6v-1.3h34.3l.1 .3a.56 .56 0 0 1 .6 .6h.3l.2-.2 .4 .1a.38 .38 0 0 0 .6 .2 .38 .38 0 0 0-.1-.6 .38 .38 0 0 0-.6 .3h-.3v-.4l-.4-.1-.1-.3h75.3l.2 .3 .3 .1a.43 .43 0 0 0 .2 .5 .43 .43 0 0 0 .6-.1l.3 .1a.38 .38 0 0 0 .6 .1 .38 .38 0 0 0-.1-.6 .38 .38 0 0 0-.5 .4h-.3l-.1-.5a.56 .56 0 0 1-.6-.6h-.3l-.3 .3h-75.3a.37 .37 0 0 0-.4-.3 .37 .37 0 0 0-.3 .4h-34.3v-1.2h8.3l.3 .3h24.8a.38 .38 0 0 0 .5 .3 .38 .38 0 0 0 .1-.6 .38 .38 0 0 0-.6 .2v.1h-24.6a.37 .37 0 0 0 0-.6 .37 .37 0 0 0-.5 .3h-8.3v-.6h5.5v.1a.37 .37 0 0 0 .5 .2 .37 .37 0 0 0 .3-.4h8.2v.2a.4 .4 0 0 0 .7 .1 .4 .4 0 0 0-.2-.7 .4 .4 0 0 0 .4-.4 .4 .4 0 0 0-.4-.4 .4 .4 0 0 0-.4 .3l.2 .5-.3 .4h-8.3a.38 .38 0 0 0-.4-.3 .38 .38 0 0 0-.3 .4h-5.5v-.5h1.4v.2a.37 .37 0 0 0 .6 .1 .37 .37 0 0 0 0-.6h6.9v.2a.38 .38 0 0 0 .6 .1 .38 .38 0 0 0-.1-.6 .38 .38 0 0 0-.5 .3h-7.1l-.4 .3h-1.4v-1.1h4.1a.37 .37 0 0 0 .4 .4 .37 .37 0 0 0 .4-.3l.3 .1a.37 .37 0 0 0 .6 .2 .37 .37 0 0 0 0-.6h34.2l.1 .1a.57 .57 0 0 0 .7 .2h.7a.47 .47 0 0 0 .1 .5 .47 .47 0 0 0 .5 .2l.1-.5h22v2.3l.4 .4h2.9l.4-.4v-1.1h1.8v.2a1.56 1.56 0 0 0 1.4 1.3l1.2-.1 .7-.4h36.4v.1a.38 .38 0 0 0 .6 .1 .38 .38 0 0 0-.1-.6 .38 .38 0 0 0-.5 .4h-36.4l.2-.4h11a.38 .38 0 0 0 .5 .3 .38 .38 0 0 0 .1-.6 .38 .38 0 0 0-.6 .2v.1h-11l.1-1h4.1l.4 .4 .3-.2h3.4l.3 .4 .4-.2h8.3l.1 .1a.4 .4 0 0 0 .6 .1 .4 .4 0 0 0-.1-.6 .4 .4 0 0 0 .3-.4 .4 .4 0 0 0-.3-.4 .4 .4 0 0 0-.5 .3l.3 .4-.4 .5h-8.3a.37 .37 0 0 0-.3-.5 .37 .37 0 0 0-.4 .3h-3.4l-.1-.5h7v.1a.38 .38 0 0 0 .6 .2 .38 .38 0 0 0-.1-.6 .38 .38 0 0 0-.5 .3l-7.2-.1-.4 .4h-4.1l-.3-.6-.5-.4h7.3a.37 .37 0 0 0 .4 .4 .37 .37 0 0 0 .3-.5h.9v.1a.37 .37 0 0 0 .5 .2 .37 .37 0 0 0 .1-.5h34.1v.1a.57 .57 0 0 0 .8 .2h.6a.42 .42 0 0 0 .1 .6 .42 .42 0 0 0 .6-.3v-.2h22v2.4l.4 .4h3l.3-.4v-1.1h1.8a1.56 1.56 0 0 0 1.5 1.5h.7a1.55 1.55 0 0 0 1.5-1.6 1.55 1.55 0 0 0-1.4-1.5h-.8a1.55 1.55 0 0 0-1.5 1.6h-1.8v-1.3l-.4-.3h-2.9l-.4 .3h-22l-.1-.7a.43 .43 0 0 0 .1-.6 .43 .43 0 0 0-.6-.1l-.3-.1-.4 .2a.46 .46 0 0 0-.6-.1 .46 .46 0 0 0-.1 .7l-.1 .3-34.4-.1-.3 .3h-.9a.38 .38 0 0 0-.4-.3 .38 .38 0 0 0-.3 .4h-7.3l-.5-.2h-1a1.55 1.55 0 0 0-1.3 1.4v.2h-1.8v-1.2l-.4-.4h-3l-.3 .4h-22l-.2-.2v-.5a.43 .43 0 0 0 .2-.6 .43 .43 0 0 0-.6-.2h-.4l-.4 .1a.43 .43 0 0 0-.6 0 .43 .43 0 0 0 0 .6l-.2 .3-34.4-.1-.4 .4-.3-.1a.38 .38 0 0 0-.4-.3 .38 .38 0 0 0-.4 .3h-4.1v-2h9.4l.2 .5 .5 .3a.86 .86 0 0 0 1-.7 .86 .86 0 0 0-.7-1 .86 .86 0 0 0-1 .9h-9.4v-1.1h13.8l.4 .4h50a1.55 1.55 0 0 0 1.4 1.5h.8a1.54 1.54 0 0 0 1.4-1.3l1.6 .1a1.82 1.82 0 0 0 1.9 1.5h.5a1.84 1.84 0 0 0 1.8-1.2h11.9l.2 .5 .5 .3a.86 .86 0 0 0 1-.6 .86 .86 0 0 0-.7-1 .86 .86 0 0 0-1 .6v.2h-11.9v-.4h-1.8v1.6h-.5v-1.6h-3.5v-.5l22-.1 .4 .4h50a1.55 1.55 0 0 0 1.5 1.5h.7a1.54 1.54 0 0 0 1.5-1.3h1.5a1.82 1.82 0 0 0 1.9 1.5l.5 .1a1.81 1.81 0 0 0 1.9-1.6h-1.9v1.5h-.5v-1.5h-3.4v-.6h5.8a1.81 1.81 0 0 0-1.9-1.6v1.6h-.5v-1.6a1.84 1.84 0 0 0-1.9 1.6h-1.5a1.56 1.56 0 0 0-1.4-1.2h-.8a1.55 1.55 0 0 0-1.5 1.6h-49.9l.3-.4h29.5l.1 .1a.52 .52 0 0 0 .8 .1l.3 .1 .2-.1a.5 .5 0 0 0 .8-.2l-.1-.4a.44 .44 0 0 0 0-.6 .44 .44 0 0 0-.6 0l-.3-.1-.4 .1a.44 .44 0 0 0-.6 0 .44 .44 0 0 0 0 .6l-.2 .4-29.5-.1a.38 .38 0 0 0-.4-.3 .38 .38 0 0 0-.4 .4h-16.2l-.1-.4h29.7v.1a.37 .37 0 0 0 .5 .2 .37 .37 0 0 0 .2-.5h6v.1a.38 .38 0 0 0 .6 .1 .38 .38 0 0 0-.1-.6 .38 .38 0 0 0-.5 .4h-6l-.3-.2-.4 .4-29.7-.1a1.82 1.82 0 0 0-1.7-1v1.6h-.5v-1.6a1.84 1.84 0 0 0-1.9 1.6h-1.6a1.55 1.55 0 0 0-1.3-1.3h-.8a1.55 1.55 0 0 0-1.5 1.6h-50l.3-.4h29.6a.44 .44 0 0 0 .3 .4 .44 .44 0 0 0 .5-.2l.3 .2 .3-.2a.44 .44 0 0 0 .7 .1 .44 .44 0 0 0 0-.7 .42 .42 0 0 0-.1-.6 .42 .42 0 0 0-.6 .1l-.3-.2-.3 .2a.44 .44 0 0 0-.7-.1 .44 .44 0 0 0 0 .7l-.1 .3-29.6-.1a.38 .38 0 0 0-.4-.2 .38 .38 0 0 0-.3 .3h-13.8v-.4h27.2v.1a.38 .38 0 0 0 .6 .2 .38 .38 0 0 0-.1-.6 .38 .38 0 0 0-.5 .3h-27.2v-1.1h9.4l.3 .6 .5 .3 .4-.1 .4-.3h22.4v.2a.38 .38 0 0 0 .6 .1 .38 .38 0 0 0-.1-.6 .38 .38 0 0 0-.5 .3h-22.4l.2-.5h2.7v.1a.37 .37 0 0 0 .5 .2 .37 .37 0 0 0 .3-.3h70.8l.3 .6 .6 .2a.86 .86 0 0 0 .8-.6v-.3h2.8a.38 .38 0 0 0 .5 .4 .38 .38 0 0 0 .1-.6 .38 .38 0 0 0-.6 .1v.1h-2.8a.86 .86 0 0 0-.9-.8 .86 .86 0 0 0-.8 .9h-70.8v-.1a.38 .38 0 0 0-.5-.3 .38 .38 0 0 0-.3 .4h-2.7l-.1-.2a.86 .86 0 0 0-.9-.6 .86 .86 0 0 0-.8 .8h-9.4v-1.4h28.8v.2a.38 .38 0 0 0 .6 .1 .38 .38 0 0 0-.1-.6 .38 .38 0 0 0-.5 .3h-28.8v-1.1h9.4a.85 .85 0 0 0 .6 .8h.4a.86 .86 0 0 0 .7-.6l.1-.3h21a2.66 2.66 0 0 0 2.5 .5h4.6v.2a.98 .98 0 0 0 1.6 .5h64v.1a.38 .38 0 0 0 .6 .2 .38 .38 0 0 0-.1-.6 .38 .38 0 0 0-.5 .3h-64l.3-.6-.1-.6h44.4l.3 .7a.86 .86 0 0 0 1.1 0l.3-.7h21.1a2.68 2.68 0 0 0 2.6 .5h4.4l.1 .2a.98 .98 0 0 0 1.6 .5 .98 .98 0 0 0-.3-1.7 .98 .98 0 0 0-1.4 1h-4.4l.9-.5-1.8-1.7-1.7 1.7h-21.1l-.3-.6-.5-.2-.6 .2-.3 .6-44.4-.1a.98 .98 0 0 0-1.2-.3 .98 .98 0 0 0-.6 .9h-4.6l1-.5-1.8-1.7-1.7 1.7h-21l-.2-.4-.5-.4a.85 .85 0 0 0-1.1 .9h-9.4l.1-2.5h26.5l.4 .4 4.2-.1 .2 1 .5 .8 1.7-1.8h.7l1.7 1.7a2.68 2.68 0 0 0 .6-2h66.1l.4 .4 4.2-.1 .2 1 .5 .8 1.7-1.8h.7l1.7 1.8a2.65 2.65 0 0 0 0-3.5l-1.7 1.7h-.7l-1.7-1.7-.5 .8-.2 .9h-4.1a.37 .37 0 0 0 .1-.6 .37 .37 0 0 0-.6 .3h-66.1l-.2-.7h59.5v.1a.37 .37 0 0 0 .5 .2 .37 .37 0 0 0 .2-.5h1.1v.1a.38 .38 0 0 0 .6 .2 .38 .38 0 0 0-.1-.6 .38 .38 0 0 0-.5 .3h-1.1l-.3-.2-.4 .4h-59.5l-.2-.5h58.6a.38 .38 0 0 0 .5 .3 .38 .38 0 0 0 .1-.6 .38 .38 0 0 0-.6 .2v.1h-58.6l-.2-.2-1.7 1.7h-.7l-1.7-1.7-.5 .8-.2 .9-3.9-.1a.37 .37 0 0 0-.2-.5 .37 .37 0 0 0-.5 .3h-26.5l.1-.7h17.7a.37 .37 0 0 0 .5 .3 .37 .37 0 0 0 .1-.6h1.1l.3 .4 .8-.1a.38 .38 0 0 0 .5 .4 .38 .38 0 0 0 .1-.6 .38 .38 0 0 0-.6 .1v.1h-.5a.37 .37 0 0 0 0-.6 .37 .37 0 0 0-.6 .3l-1.4-.1-.3 .4h-17.7l.6-1.1h22.4a.37 .37 0 0 0 .4 .4 .37 .37 0 0 0 .3-.4h8.3l1.7 1.8 1.8-1.7-.1-.1h63.6l.1 .1a.37 .37 0 0 0 .3 .2 .37 .37 0 0 0 .4-.3h8.3l1.7 1.8 1.8-1.8a2.68 2.68 0 0 0-3.5 0h-8.3a.38 .38 0 0 0-.4-.4 .38 .38 0 0 0-.4 .4l-63.7-.1a2.7 2.7 0 0 0-3.3 .1h-8.3a.38 .38 0 0 0-.3-.4 .38 .38 0 0 0-.4 .4zM150 78.2h3.2v2.5h-3.2zM226.1 78.1h3.1v2.6h-3.1zM93.9 124.6h3.2v2.6h-3.2zM169.2 125.7h3.1v2.5h-3.1z"/>
<circle cx="94.2" cy="66.6" r=".3"/>
<circle cx="95.9" cy="73.4" r=".65"/>
<circle cx="95.9" cy="70.9" r=".65"/>
<circle cx="95.9" cy="76" r=".65"/>
<circle cx="97.8" cy="72.3" r=".3"/>
<circle cx="99.6" cy="71.7" r=".3"/>
<circle cx="99.8" cy="77.2" r=".3"/>
<circle cx="100.5" cy="67.9" r=".3"/>
<circle cx="100.5" cy="69.9" r=".3"/>
<circle cx="112.6" cy="69.2" r=".3"/>
<circle cx="113.3" cy="73.2" r=".3"/>
<circle cx="113.7" cy="77.5" r=".3"/>
<circle cx="113.9" cy="71.1" r=".3"/>
<circle cx="116.1" cy="79.7" r=".3"/>
<circle cx="117.9" cy="68.7" r=".35"/>
<circle cx="118.4" cy="69.9" r=".35"/>
<circle cx="118.4" cy="67.6" r=".35"/>
<circle cx="119.5" cy="67.1" r=".35"/>
<circle cx="119.5" cy="68.7" r="2.2"/>
<circle cx="119.5" cy="70.4" r=".35"/>
<circle cx="120.7" cy="69.9" r=".35"/>
<circle cx="120.7" cy="67.6" r=".35"/>
<circle cx="121" cy="78.7" r=".3"/>
<circle cx="121" cy="77.2" r=".3"/>
<circle cx="121.2" cy="68.7" r=".35"/>
<circle cx="145.7" cy="67" r=".5"/>
<circle cx="145.7" cy="68.2" r=".5"/>
<circle cx="146.8" cy="67" r=".5"/>
<circle cx="146.8" cy="68.2" r=".5"/>
<circle cx="148" cy="67.1" r=".5"/>
<circle cx="148" cy="68.2" r=".5"/>
<circle cx="172" cy="70.8" r=".65"/>
<circle cx="172" cy="75.9" r=".65"/>
<circle cx="172" cy="73.4" r=".65"/>
<circle cx="175.7" cy="71.7" r=".3"/>
<circle cx="175.8" cy="77.2" r=".3"/>
<circle cx="176.5" cy="67.9" r=".3"/>
<circle cx="176.6" cy="69.9" r=".3"/>
<circle cx="188.5" cy="79.8" r=".3"/>
<circle cx="188.6" cy="69.2" r=".3"/>
<circle cx="189.8" cy="77.5" r=".3"/>
<circle cx="189.9" cy="71.1" r=".3"/>
<circle cx="192.2" cy="79.6" r=".3"/>
<circle cx="194" cy="68.7" r=".35"/>
<circle cx="194.5" cy="69.9" r=".35"/>
<circle cx="194.5" cy="67.6" r=".35"/>
<circle cx="195.6" cy="68.7" r="2.2"/>
<circle cx="195.6" cy="67.1" r=".35"/>
<circle cx="195.6" cy="70.4" r=".35"/>
<circle cx="196.8" cy="69.9" r=".35"/>
<circle cx="196.8" cy="67.6" r=".35"/>
<circle cx="197.3" cy="68.7" r=".35"/>
<circle cx="197.6" cy="78.5" r=".3"/>
<circle cx="197.6" cy="77.1" r=".3"/>
<circle cx="197.6" cy="79.9" r=".3"/>
<circle cx="222.6" cy="67" r=".5"/>
<circle cx="222.7" cy="68.2" r=".5"/>
<circle cx="223.8" cy="67" r=".5"/>
<circle cx="223.8" cy="68.2" r=".5"/>
<circle cx="224.9" cy="68.2" r=".5"/>
<circle cx="224.9" cy="67" r=".5"/>
<circle cx="91.3" cy="82.1" r=".3"/>
<circle cx="100.2" cy="99.2" r="1.4"/>
<circle cx="100.2" cy="86.7" r="1.45"/>
<circle cx="102.3" cy="85.2" r=".76"/>
<circle cx="102.3" cy="88.2" r=".76"/>
<circle cx="103" cy="83.9" r=".4"/>
<circle cx="104.4" cy="82.9" r=".4"/>
<circle cx="105.3" cy="85.2" r=".76"/>
<circle cx="105.3" cy="88.2" r=".76"/>
<circle cx="105.7" cy="99.2" r="1.4"/>
<circle cx="105.8" cy="82.7" r=".4"/>
<circle cx="106.6" cy="92.8" r=".4"/>
<circle cx="106.7" cy="83.8" r=".4"/>
<circle cx="107.3" cy="91.2" r=".4"/>
<circle cx="107.3" cy="94.4" r=".4"/>
<circle cx="107.7" cy="82.5" r=".4"/>
<circle cx="108.3" cy="85.2" r=".76"/>
<circle cx="108.3" cy="88.2" r=".76"/>
<circle cx="108.8" cy="92.8" r="3"/>
<circle cx="108.8" cy="95" r=".4"/>
<circle cx="108.8" cy="90.5" r=".4"/>
<circle cx="110.4" cy="91.2" r=".4"/>
<circle cx="110.4" cy="94.4" r=".4"/>
<circle cx="110.5" cy="86.7" r="1.45"/>
<circle cx="111.1" cy="92.8" r=".4"/>
<circle cx="119.5" cy="86.2" r=".3"/>
<circle cx="119.8" cy="83.8" r=".3"/>
<circle cx="120.9" cy="80.1" r=".3"/>
<circle cx="121.8" cy="82.9" r=".3"/>
<circle cx="137.6" cy="81.5" r=".3"/>
<circle cx="149.6" cy="97.6" r=".3"/>
<circle cx="152.2" cy="93.3" r=".3"/>
<circle cx="152.2" cy="91.8" r=".3"/>
<circle cx="154.4" cy="85.7" r=".5"/>
<circle cx="154.4" cy="83" r=".5"/>
<circle cx="154.4" cy="84.3" r=".5"/>
<circle cx="154.9" cy="90.8" r=".3"/>
<circle cx="167.6" cy="81.2" r=".3"/>
<circle cx="176.1" cy="86.7" r="1.46"/>
<circle cx="178.3" cy="85.2" r=".76"/>
<circle cx="178.3" cy="88.2" r=".76"/>
<circle cx="181.3" cy="85.2" r=".76"/>
<circle cx="181.3" cy="88.2" r=".76"/>
<circle cx="182.7" cy="92.8" r=".4"/>
<circle cx="183.4" cy="91.2" r=".4"/>
<circle cx="183.4" cy="94.4" r=".4"/>
<circle cx="184.3" cy="85.2" r=".76"/>
<circle cx="184.3" cy="88.2" r=".76"/>
<circle cx="184.9" cy="92.8" r="3"/>
<circle cx="184.9" cy="95" r=".4"/>
<circle cx="184.9" cy="90.5" r=".4"/>
<circle cx="186.4" cy="86.7" r="1.46"/>
<circle cx="186.5" cy="91.2" r=".4"/>
<circle cx="186.5" cy="94.4" r=".4"/>
<circle cx="187.2" cy="92.8" r=".4"/>
<circle cx="195" cy="86" r=".3"/>
<circle cx="195.4" cy="82.8" r=".3"/>
<circle cx="198.1" cy="85.3" r=".3"/>
<circle cx="199.5" cy="84.4" r=".3"/>
<circle cx="213.7" cy="81.5" r=".3"/>
<circle cx="228.3" cy="98.1" r=".3"/>
<circle cx="230.2" cy="85.2" r=".5"/>
<circle cx="230.2" cy="86.8" r=".5"/>
<circle cx="230.3" cy="83.6" r=".5"/>
<circle cx="230.8" cy="94.5" r=".3"/>
<circle cx="230.8" cy="91.7" r=".3"/>
<circle cx="231.5" cy="83" r=".5"/>
<circle cx="233.1" cy="83" r=".5"/>
<circle cx="90" cy="112.1" r=".3"/>
<circle cx="94.8" cy="119.6" r=".5"/>
<circle cx="96" cy="119.6" r=".5"/>
<circle cx="97.1" cy="119.6" r=".5"/>
<circle cx="97.5" cy="112.7" r=".3"/>
<circle cx="101" cy="109.4" r=".4"/>
<circle cx="103.9" cy="107.6" r=".3"/>
<circle cx="109.5" cy="117.4" r=".3"/>
<circle cx="115" cy="112.1" r=".3"/>
<circle cx="117.2" cy="116.9" r=".3"/>
<circle cx="123.3" cy="110.3" r=".3"/>
<circle cx="136.1" cy="112.5" r=".4"/>
<circle cx="136.8" cy="119.6" r="1.45"/>
<circle cx="136.8" cy="110.9" r=".4"/>
<circle cx="136.8" cy="114.1" r=".4"/>
<circle cx="138.4" cy="112.5" r="3"/>
<circle cx="138.4" cy="114.7" r=".4"/>
<circle cx="138.4" cy="110.2" r=".4"/>
<circle cx="138.9" cy="118.1" r=".76"/>
<circle cx="140" cy="110.9" r=".4"/>
<circle cx="140" cy="114.1" r=".4"/>
<circle cx="140.6" cy="112.5" r=".4"/>
<circle cx="141.9" cy="118.1" r=".76"/>
<circle cx="144.9" cy="118.1" r=".76"/>
<circle cx="145.9" cy="114.8" r=".3"/>
<circle cx="146.4" cy="115.5" r=".4"/>
<circle cx="147.1" cy="119.6" r="1.46"/>
<circle cx="160.2" cy="112.9" r=".3"/>
<circle cx="165.1" cy="108.2" r=".3"/>
<circle cx="165.2" cy="110.1" r=".4"/>
<circle cx="167.6" cy="119.4" r=".5"/>
<circle cx="168.8" cy="119.4" r=".5"/>
<circle cx="172.7" cy="112.8" r=".3"/>
<circle cx="176.3" cy="107.6" r=".3"/>
<circle cx="180.5" cy="111" r=".4"/>
<circle cx="184.4" cy="109.5" r=".4"/>
<circle cx="184.7" cy="117.4" r=".3"/>
<circle cx="184.7" cy="110.6" r=".3"/>
<circle cx="190.1" cy="109.2" r=".3"/>
<circle cx="190.7" cy="111.6" r=".3"/>
<circle cx="198.9" cy="115" r=".3"/>
<circle cx="203" cy="118.1" r=".3"/>
<circle cx="211.3" cy="112.6" r=".4"/>
<circle cx="212" cy="114.2" r=".4"/>
<circle cx="212" cy="111" r=".4"/>
<circle cx="212" cy="119.7" r="1.45"/>
<circle cx="213.5" cy="112.6" r="3"/>
<circle cx="213.5" cy="110.3" r=".4"/>
<circle cx="213.5" cy="114.8" r=".4"/>
<circle cx="214.1" cy="118.2" r=".76"/>
<circle cx="215.1" cy="114.2" r=".4"/>
<circle cx="215.1" cy="111" r=".4"/>
<circle cx="215.8" cy="112.6" r=".4"/>
<circle cx="217.1" cy="118.2" r=".76"/>
<circle cx="218.7" cy="119.6" r=".3"/>
<circle cx="220.1" cy="118.2" r=".76"/>
<circle cx="222.3" cy="119.7" r="1.46"/>
<circle cx="223" cy="109.4" r="1.27"/>
<circle cx="223" cy="104.4" r="1.28"/>
<circle cx="233" cy="101.4" r=".75"/>
<circle cx="233" cy="112.4" r=".75"/>
<circle cx="109.5" cy="124.8" r=".3"/>
<circle cx="116.9" cy="120.7" r=".3"/>
<circle cx="123.8" cy="126.1" r=".3"/>
<circle cx="123.8" cy="126.8" r=".3"/>
<circle cx="124.4" cy="126.5" r=".3"/>
<circle cx="125.1" cy="121" r=".3"/>
<circle cx="125.1" cy="126.1" r=".3"/>
<circle cx="125.1" cy="126.8" r=".3"/>
<circle cx="125.3" cy="123.4" r=".3"/>
<circle cx="125.7" cy="137.7" r=".35"/>
<circle cx="126.2" cy="138.9" r=".35"/>
<circle cx="126.2" cy="136.6" r=".35"/>
<circle cx="127.4" cy="137.7" r="2.2"/>
<circle cx="127.4" cy="136.1" r=".35"/>
<circle cx="127.4" cy="139.4" r=".35"/>
<circle cx="127.6" cy="120.1" r=".3"/>
<circle cx="127.8" cy="123.5" r=".3"/>
<circle cx="128.6" cy="138.9" r=".35"/>
<circle cx="128.6" cy="136.6" r=".35"/>
<circle cx="129" cy="137.7" r=".35"/>
<circle cx="131" cy="126.7" r=".3"/>
<circle cx="133.3" cy="135.2" r=".3"/>
<circle cx="133.9" cy="129.1" r=".3"/>
<circle cx="134.6" cy="137.1" r=".3"/>
<circle cx="138.9" cy="121.1" r=".76"/>
<circle cx="141.9" cy="121.1" r=".76"/>
<circle cx="142.8" cy="137.7" r=".3"/>
<circle cx="144" cy="138.4" r=".3"/>
<circle cx="144.9" cy="121.1" r=".76"/>
<circle cx="146.6" cy="136.5" r=".3"/>
<circle cx="147.4" cy="128.2" r=".3"/>
<circle cx="147.5" cy="134.6" r=".3"/>
<circle cx="151.3" cy="130.4" r=".65"/>
<circle cx="151.3" cy="132.9" r=".65"/>
<circle cx="151.3" cy="135.5" r=".65"/>
<circle cx="155.8" cy="124.2" r=".3"/>
<circle cx="168.8" cy="121.7" r=".5"/>
<circle cx="168.8" cy="120.5" r=".5"/>
<circle cx="174.4" cy="138.2" r=".5"/>
<circle cx="174.4" cy="139.3" r=".5"/>
<circle cx="175.5" cy="138.2" r=".5"/>
<circle cx="175.5" cy="139.4" r=".5"/>
<circle cx="184.7" cy="124.9" r=".3"/>
<circle cx="198.9" cy="127.7" r=".3"/>
<circle cx="198.9" cy="126.3" r=".3"/>
<circle cx="198.9" cy="127" r=".3"/>
<circle cx="199.4" cy="123" r=".3"/>
<circle cx="199.5" cy="127.4" r=".3"/>
<circle cx="199.5" cy="126.7" r=".3"/>
<circle cx="200.3" cy="121.1" r=".3"/>
<circle cx="200.9" cy="137.7" r=".35"/>
<circle cx="201.4" cy="138.9" r=".35"/>
<circle cx="201.4" cy="136.6" r=".35"/>
<circle cx="202.5" cy="137.7" r="2.2"/>
<circle cx="202.5" cy="136.1" r=".35"/>
<circle cx="202.5" cy="139.4" r=".35"/>
<circle cx="202.9" cy="120.2" r=".3"/>
<circle cx="203" cy="123.6" r=".3"/>
<circle cx="203.7" cy="138.9" r=".35"/>
<circle cx="203.7" cy="136.6" r=".35"/>
<circle cx="204.2" cy="137.7" r=".35"/>
<circle cx="206.3" cy="126.7" r=".3"/>
<circle cx="208.3" cy="131" r=".3"/>
<circle cx="208.5" cy="135.3" r=".3"/>
<circle cx="208.6" cy="128.8" r=".3"/>
<circle cx="208.9" cy="133.3" r=".3"/>
<circle cx="209.8" cy="137.1" r=".3"/>
<circle cx="214.1" cy="121.2" r=".76"/>
<circle cx="216.6" cy="123.8" r=".3"/>
<circle cx="217.1" cy="121.2" r=".76"/>
<circle cx="220.1" cy="121.2" r=".76"/>
<circle cx="221.8" cy="136.5" r=".3"/>
<circle cx="222" cy="138.2" r=".3"/>
<circle cx="222.7" cy="129.2" r=".3"/>
<circle cx="222.7" cy="134.7" r=".3"/>
<circle cx="226.5" cy="139.3" r=".3"/>
<circle cx="226.5" cy="135.5" r=".65"/>
<circle cx="226.5" cy="130.4" r=".65"/>
<circle cx="226.5" cy="133" r=".65"/>
<circle cx="230.4" cy="131.3" r=".4"/>
<circle cx="236" cy="128.1" r=".3"/>
</g>
<path d="M151.3 75.2h.6M156.8 75.2h.6M156.8 79.4h.6M227.4 75.2h.6M232.9 75.2h.6M232.9 79.4h.6M89.7 130.1h.6M89.7 125.9h.6M95.2 130.1h.6M165 131.1h.6M165 126.9h.6M170.5 131.1h.6" fill="none" stroke="#000" stroke-width="2.7"/>
<path d="M114.8 89.1h.7M117.4 91.2h1.1M120.4 89.1h.7M190.8 89h.7M193.4 91.2h1.1M196.4 89h.7M126.1 117.3h.7M128.7 115.1h1.1M131.7 117.3h.7M201.3 117.3h.7M203.9 115.2h1.1M206.9 117.3h.7" fill="none" stroke="#000" stroke-width="1.1"/>
</svg>
